One B-rep face of a CAD part: STEP entity #70354.
In plain terms, the planar face has unit normal (0, 0, 1).
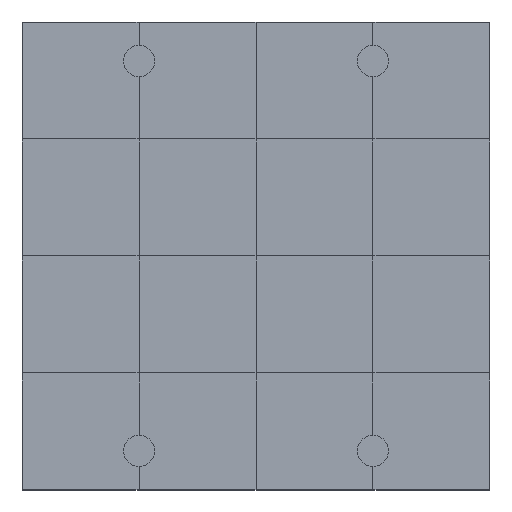
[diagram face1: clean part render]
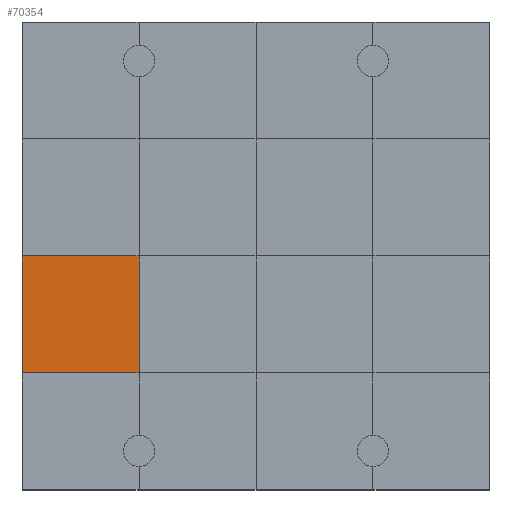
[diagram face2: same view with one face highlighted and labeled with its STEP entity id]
Its self-contained STEP definition (entity closure, numbers rounded to 3 decimals):
#69904 = VERTEX_POINT('',#69905);
#69905 = CARTESIAN_POINT('',(0.,3.,1.2));
#69919 = PLANE('',#69920);
#69920 = AXIS2_PLACEMENT_3D('',#69921,#69922,#69923);
#69921 = CARTESIAN_POINT('',(0.,3.,0.));
#69922 = DIRECTION('',(1.,0.,-0.));
#69923 = DIRECTION('',(0.,0.,1.));
#69945 = PLANE('',#69946);
#69946 = AXIS2_PLACEMENT_3D('',#69947,#69948,#69949);
#69947 = CARTESIAN_POINT('',(0.,0.,1.2));
#69948 = DIRECTION('',(0.,0.,1.));
#69949 = DIRECTION('',(1.,0.,-0.));
#70096 = VERTEX_POINT('',#70097);
#70097 = CARTESIAN_POINT('',(3.,3.,1.2));
#70118 = EDGE_CURVE('',#69904,#70096,#70119,.T.);
#70119 = SURFACE_CURVE('',#70120,(#70124,#70131),.PCURVE_S1.);
#70120 = LINE('',#70121,#70122);
#70121 = CARTESIAN_POINT('',(0.,3.,1.2));
#70122 = VECTOR('',#70123,1.);
#70123 = DIRECTION('',(1.,0.,-0.));
#70124 = PCURVE('',#69945,#70125);
#70125 = DEFINITIONAL_REPRESENTATION('',(#70126),#70130);
#70126 = LINE('',#70127,#70128);
#70127 = CARTESIAN_POINT('',(0.,3.));
#70128 = VECTOR('',#70129,1.);
#70129 = DIRECTION('',(1.,0.));
#70130 = ( GEOMETRIC_REPRESENTATION_CONTEXT(2) 
PARAMETRIC_REPRESENTATION_CONTEXT() REPRESENTATION_CONTEXT('2D SPACE',''
  ) );
#70131 = PCURVE('',#70132,#70137);
#70132 = PLANE('',#70133);
#70133 = AXIS2_PLACEMENT_3D('',#70134,#70135,#70136);
#70134 = CARTESIAN_POINT('',(0.,3.,1.2));
#70135 = DIRECTION('',(0.,0.,1.));
#70136 = DIRECTION('',(1.,0.,-0.));
#70137 = DEFINITIONAL_REPRESENTATION('',(#70138),#70142);
#70138 = LINE('',#70139,#70140);
#70139 = CARTESIAN_POINT('',(0.,0.));
#70140 = VECTOR('',#70141,1.);
#70141 = DIRECTION('',(1.,0.));
#70142 = ( GEOMETRIC_REPRESENTATION_CONTEXT(2) 
PARAMETRIC_REPRESENTATION_CONTEXT() REPRESENTATION_CONTEXT('2D SPACE',''
  ) );
#70177 = VERTEX_POINT('',#70178);
#70178 = CARTESIAN_POINT('',(0.,6.,1.2));
#70204 = EDGE_CURVE('',#69904,#70177,#70205,.T.);
#70205 = SURFACE_CURVE('',#70206,(#70210,#70217),.PCURVE_S1.);
#70206 = LINE('',#70207,#70208);
#70207 = CARTESIAN_POINT('',(0.,3.,1.2));
#70208 = VECTOR('',#70209,1.);
#70209 = DIRECTION('',(-0.,1.,0.));
#70210 = PCURVE('',#69919,#70211);
#70211 = DEFINITIONAL_REPRESENTATION('',(#70212),#70216);
#70212 = LINE('',#70213,#70214);
#70213 = CARTESIAN_POINT('',(1.2,0.));
#70214 = VECTOR('',#70215,1.);
#70215 = DIRECTION('',(0.,-1.));
#70216 = ( GEOMETRIC_REPRESENTATION_CONTEXT(2) 
PARAMETRIC_REPRESENTATION_CONTEXT() REPRESENTATION_CONTEXT('2D SPACE',''
  ) );
#70217 = PCURVE('',#70132,#70218);
#70218 = DEFINITIONAL_REPRESENTATION('',(#70219),#70223);
#70219 = LINE('',#70220,#70221);
#70220 = CARTESIAN_POINT('',(0.,0.));
#70221 = VECTOR('',#70222,1.);
#70222 = DIRECTION('',(0.,1.));
#70223 = ( GEOMETRIC_REPRESENTATION_CONTEXT(2) 
PARAMETRIC_REPRESENTATION_CONTEXT() REPRESENTATION_CONTEXT('2D SPACE',''
  ) );
#70354 = ADVANCED_FACE('',(#70355),#70132,.T.);
#70355 = FACE_BOUND('',#70356,.T.);
#70356 = EDGE_LOOP('',(#70357,#70358,#70359,#70387));
#70357 = ORIENTED_EDGE('',*,*,#70204,.F.);
#70358 = ORIENTED_EDGE('',*,*,#70118,.T.);
#70359 = ORIENTED_EDGE('',*,*,#70360,.T.);
#70360 = EDGE_CURVE('',#70096,#70361,#70363,.T.);
#70361 = VERTEX_POINT('',#70362);
#70362 = CARTESIAN_POINT('',(3.,6.,1.2));
#70363 = SURFACE_CURVE('',#70364,(#70368,#70375),.PCURVE_S1.);
#70364 = LINE('',#70365,#70366);
#70365 = CARTESIAN_POINT('',(3.,3.,1.2));
#70366 = VECTOR('',#70367,1.);
#70367 = DIRECTION('',(-0.,1.,0.));
#70368 = PCURVE('',#70132,#70369);
#70369 = DEFINITIONAL_REPRESENTATION('',(#70370),#70374);
#70370 = LINE('',#70371,#70372);
#70371 = CARTESIAN_POINT('',(3.,0.));
#70372 = VECTOR('',#70373,1.);
#70373 = DIRECTION('',(0.,1.));
#70374 = ( GEOMETRIC_REPRESENTATION_CONTEXT(2) 
PARAMETRIC_REPRESENTATION_CONTEXT() REPRESENTATION_CONTEXT('2D SPACE',''
  ) );
#70375 = PCURVE('',#70376,#70381);
#70376 = PLANE('',#70377);
#70377 = AXIS2_PLACEMENT_3D('',#70378,#70379,#70380);
#70378 = CARTESIAN_POINT('',(3.,3.,1.2));
#70379 = DIRECTION('',(0.,0.,1.));
#70380 = DIRECTION('',(1.,0.,-0.));
#70381 = DEFINITIONAL_REPRESENTATION('',(#70382),#70386);
#70382 = LINE('',#70383,#70384);
#70383 = CARTESIAN_POINT('',(0.,0.));
#70384 = VECTOR('',#70385,1.);
#70385 = DIRECTION('',(0.,1.));
#70386 = ( GEOMETRIC_REPRESENTATION_CONTEXT(2) 
PARAMETRIC_REPRESENTATION_CONTEXT() REPRESENTATION_CONTEXT('2D SPACE',''
  ) );
#70387 = ORIENTED_EDGE('',*,*,#70388,.F.);
#70388 = EDGE_CURVE('',#70177,#70361,#70389,.T.);
#70389 = SURFACE_CURVE('',#70390,(#70394,#70401),.PCURVE_S1.);
#70390 = LINE('',#70391,#70392);
#70391 = CARTESIAN_POINT('',(0.,6.,1.2));
#70392 = VECTOR('',#70393,1.);
#70393 = DIRECTION('',(1.,0.,-0.));
#70394 = PCURVE('',#70132,#70395);
#70395 = DEFINITIONAL_REPRESENTATION('',(#70396),#70400);
#70396 = LINE('',#70397,#70398);
#70397 = CARTESIAN_POINT('',(0.,3.));
#70398 = VECTOR('',#70399,1.);
#70399 = DIRECTION('',(1.,0.));
#70400 = ( GEOMETRIC_REPRESENTATION_CONTEXT(2) 
PARAMETRIC_REPRESENTATION_CONTEXT() REPRESENTATION_CONTEXT('2D SPACE',''
  ) );
#70401 = PCURVE('',#70402,#70407);
#70402 = PLANE('',#70403);
#70403 = AXIS2_PLACEMENT_3D('',#70404,#70405,#70406);
#70404 = CARTESIAN_POINT('',(0.,6.,1.2));
#70405 = DIRECTION('',(0.,0.,1.));
#70406 = DIRECTION('',(1.,0.,-0.));
#70407 = DEFINITIONAL_REPRESENTATION('',(#70408),#70412);
#70408 = LINE('',#70409,#70410);
#70409 = CARTESIAN_POINT('',(0.,0.));
#70410 = VECTOR('',#70411,1.);
#70411 = DIRECTION('',(1.,0.));
#70412 = ( GEOMETRIC_REPRESENTATION_CONTEXT(2) 
PARAMETRIC_REPRESENTATION_CONTEXT() REPRESENTATION_CONTEXT('2D SPACE',''
  ) );
